VERSION 5.7 ;
  NOWIREEXTENSIONATPIN ON ;
  DIVIDERCHAR "/" ;
  BUSBITCHARS "[]" ;
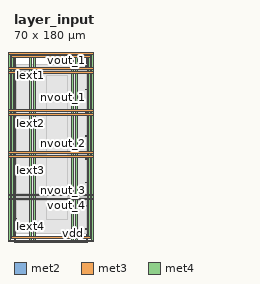
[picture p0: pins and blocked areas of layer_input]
MACRO layer_input
  CLASS BLOCK ;
  FOREIGN layer_input ;
  ORIGIN 0.000 0.000 ;
  SIZE 70.000 BY 180.000 ;
  PIN Iext1
    DIRECTION INPUT ;
    USE SIGNAL ;
    ANTENNAGATEAREA 0.280000 ;
    ANTENNADIFFAREA 1.170000 ;
    PORT
      LAYER met2 ;
        RECT 0.000 157.340 2.500 157.760 ;
    END
  END Iext1
  PIN Iext2
    DIRECTION INPUT ;
    USE SIGNAL ;
    ANTENNAGATEAREA 0.280000 ;
    ANTENNADIFFAREA 1.170000 ;
    PORT
      LAYER met2 ;
        RECT 0.000 112.260 2.500 112.680 ;
    END
  END Iext2
  PIN Iext3
    DIRECTION INPUT ;
    USE SIGNAL ;
    ANTENNAGATEAREA 0.280000 ;
    ANTENNADIFFAREA 1.170000 ;
    PORT
      LAYER met2 ;
        RECT 0.000 67.180 2.500 67.600 ;
    END
  END Iext3
  PIN Iext4
    DIRECTION INPUT ;
    USE SIGNAL ;
    ANTENNAGATEAREA 0.280000 ;
    ANTENNADIFFAREA 1.170000 ;
    PORT
      LAYER met2 ;
        RECT 0.000 22.100 2.500 22.520 ;
    END
  END Iext4
  PIN nvout_1
    DIRECTION OUTPUT ;
    USE SIGNAL ;
    ANTENNAGATEAREA 0.560000 ;
    ANTENNADIFFAREA 0.390000 ;
    PORT
      LAYER met2 ;
        RECT 67.500 144.460 70.000 144.880 ;
    END
  END nvout_1
  PIN nvout_2
    DIRECTION OUTPUT ;
    USE SIGNAL ;
    ANTENNAGATEAREA 0.560000 ;
    ANTENNADIFFAREA 0.390000 ;
    PORT
      LAYER met2 ;
        RECT 67.500 100.300 70.000 100.720 ;
    END
  END nvout_2
  PIN nvout_3
    DIRECTION OUTPUT ;
    USE SIGNAL ;
    ANTENNAGATEAREA 0.560000 ;
    ANTENNADIFFAREA 0.390000 ;
    PORT
      LAYER met2 ;
        RECT 67.500 56.140 70.000 56.560 ;
    END
  END nvout_3
  PIN nvout_4
    DIRECTION OUTPUT ;
    USE SIGNAL ;
    ANTENNAGATEAREA 0.560000 ;
    ANTENNADIFFAREA 0.390000 ;
    PORT
      LAYER met2 ;
        RECT 67.500 11.980 70.000 12.400 ;
    END
  END nvout_4
  PIN vdd
    DIRECTION INOUT ;
    USE POWER ;
    PORT
      LAYER met3 ;
        RECT -2.080 3.280 72.000 4.880 ;
    END
    PORT
      LAYER met3 ;
        RECT -2.080 174.640 72.000 176.240 ;
    END
    PORT
      LAYER met4 ;
        RECT -2.080 3.280 -0.480 176.240 ;
    END
    PORT
      LAYER met4 ;
        RECT 70.400 3.280 72.000 176.240 ;
    END
    PORT
      LAYER met3 ;
        RECT -5.280 40.080 75.200 41.680 ;
    END
    PORT
      LAYER met3 ;
        RECT -5.280 80.080 75.200 81.680 ;
    END
    PORT
      LAYER met3 ;
        RECT -5.280 120.080 75.200 121.680 ;
    END
    PORT
      LAYER met3 ;
        RECT -5.280 160.080 75.200 161.680 ;
    END
    PORT
      LAYER met4 ;
        RECT 14.720 0.080 16.320 179.440 ;
    END
    PORT
      LAYER met4 ;
        RECT 54.720 0.080 56.320 179.440 ;
    END
  END vdd
  PIN vout_1
    DIRECTION OUTPUT ;
    USE SIGNAL ;
    ANTENNADIFFAREA 0.390000 ;
    PORT
      LAYER met2 ;
        RECT 67.500 166.540 70.000 166.960 ;
    END
  END vout_1
  PIN vout_2
    DIRECTION OUTPUT ;
    USE SIGNAL ;
    ANTENNADIFFAREA 0.390000 ;
    PORT
      LAYER met2 ;
        RECT 67.500 122.380 70.000 122.800 ;
    END
  END vout_2
  PIN vout_3
    DIRECTION OUTPUT ;
    USE SIGNAL ;
    ANTENNADIFFAREA 0.390000 ;
    PORT
      LAYER met2 ;
        RECT 67.500 78.220 70.000 78.640 ;
    END
  END vout_3
  PIN vout_4
    DIRECTION OUTPUT ;
    USE SIGNAL ;
    ANTENNADIFFAREA 0.390000 ;
    PORT
      LAYER met2 ;
        RECT 67.500 34.060 70.000 34.480 ;
    END
  END vout_4
  PIN vss
    DIRECTION INOUT ;
    USE GROUND ;
    PORT
      LAYER met3 ;
        RECT -5.280 0.080 75.200 1.680 ;
    END
    PORT
      LAYER met3 ;
        RECT -5.280 177.840 75.200 179.440 ;
    END
    PORT
      LAYER met4 ;
        RECT -5.280 0.080 -3.680 179.440 ;
    END
    PORT
      LAYER met4 ;
        RECT 73.600 0.080 75.200 179.440 ;
    END
    PORT
      LAYER met3 ;
        RECT -5.280 43.680 75.200 45.280 ;
    END
    PORT
      LAYER met3 ;
        RECT -5.280 83.680 75.200 85.280 ;
    END
    PORT
      LAYER met3 ;
        RECT -5.280 123.680 75.200 125.280 ;
    END
    PORT
      LAYER met3 ;
        RECT -5.280 163.680 75.200 165.280 ;
    END
    PORT
      LAYER met4 ;
        RECT 18.320 0.080 19.920 179.440 ;
    END
    PORT
      LAYER met4 ;
        RECT 58.320 0.080 59.920 179.440 ;
    END
  END vss
  OBS
      LAYER nwell ;
        RECT 12.000 12.450 50.840 145.800 ;
      LAYER li1 ;
        RECT 12.310 12.580 50.710 145.440 ;
      LAYER met1 ;
        RECT 10.950 10.555 52.315 149.190 ;
      LAYER met2 ;
        RECT 1.930 167.240 68.450 167.805 ;
        RECT 1.930 166.260 67.220 167.240 ;
        RECT 1.930 158.040 68.450 166.260 ;
        RECT 2.780 157.060 68.450 158.040 ;
        RECT 1.930 145.160 68.450 157.060 ;
        RECT 1.930 144.180 67.220 145.160 ;
        RECT 1.930 123.080 68.450 144.180 ;
        RECT 1.930 122.100 67.220 123.080 ;
        RECT 1.930 112.960 68.450 122.100 ;
        RECT 2.780 111.980 68.450 112.960 ;
        RECT 1.930 101.000 68.450 111.980 ;
        RECT 1.930 100.020 67.220 101.000 ;
        RECT 1.930 78.920 68.450 100.020 ;
        RECT 1.930 77.940 67.220 78.920 ;
        RECT 1.930 67.880 68.450 77.940 ;
        RECT 2.780 66.900 68.450 67.880 ;
        RECT 1.930 56.840 68.450 66.900 ;
        RECT 1.930 55.860 67.220 56.840 ;
        RECT 1.930 34.760 68.450 55.860 ;
        RECT 1.930 33.780 67.220 34.760 ;
        RECT 1.930 22.800 68.450 33.780 ;
        RECT 2.780 21.820 68.450 22.800 ;
        RECT 1.930 12.680 68.450 21.820 ;
        RECT 1.930 11.700 67.220 12.680 ;
        RECT 1.930 8.315 68.450 11.700 ;
      LAYER met3 ;
        RECT 1.905 165.680 68.475 167.785 ;
        RECT 1.905 162.080 68.475 163.280 ;
        RECT 1.905 125.680 68.475 159.680 ;
        RECT 1.905 122.080 68.475 123.280 ;
        RECT 1.905 85.680 68.475 119.680 ;
        RECT 1.905 82.080 68.475 83.280 ;
        RECT 1.905 45.680 68.475 79.680 ;
        RECT 1.905 42.080 68.475 43.280 ;
        RECT 1.905 8.335 68.475 39.680 ;
      LAYER met4 ;
        RECT 30.560 20.875 50.725 157.585 ;
  END
END layer_input
END LIBRARY

